VERSION 5.8 ;
BUSBITCHARS "[]" ;
DIVIDERCHAR "/" ;
UNITS
    DATABASE MICRONS 1000 ;
END UNITS

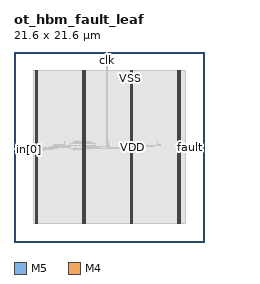
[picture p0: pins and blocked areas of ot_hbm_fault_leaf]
MACRO ot_hbm_fault_leaf
  FOREIGN ot_hbm_fault_leaf 0 0 ;
  CLASS BLOCK ;
  SIZE 21.6 BY 21.6 ;
  PIN clk
    DIRECTION INPUT ;
    USE SIGNAL ;
    PORT
      LAYER M5 ;
        RECT  10.512 21.516 10.536 21.6 ;
    END
  END clk
  PIN fault
    DIRECTION OUTPUT ;
    USE SIGNAL ;
    PORT
      LAYER M4 ;
        RECT  21.516 10.704 21.6 10.728 ;
    END
    PORT
      LAYER M4 ;
        RECT  21.481 10.704 21.564 10.728 ;
    END
  END fault
  PIN in[0]
    DIRECTION INPUT ;
    USE SIGNAL ;
    PORT
      LAYER M4 ;
        RECT  0 10.512 0.084 10.536 ;
    END
  END in[0]
  PIN in[1]
    DIRECTION INPUT ;
    USE SIGNAL ;
    PORT
      LAYER M4 ;
        RECT  0 10.608 0.084 10.632 ;
    END
  END in[1]
  PIN in[2]
    DIRECTION INPUT ;
    USE SIGNAL ;
    PORT
      LAYER M4 ;
        RECT  0 10.704 0.084 10.728 ;
    END
  END in[2]
  PIN in[3]
    DIRECTION INPUT ;
    USE SIGNAL ;
    PORT
      LAYER M4 ;
        RECT  0 10.8 0.084 10.824 ;
    END
  END in[3]
  PIN rst_n
    DIRECTION INPUT ;
    USE SIGNAL ;
    PORT
      LAYER M5 ;
        RECT  10.608 21.516 10.632 21.6 ;
    END
  END rst_n
  PIN VDD
    DIRECTION INOUT ;
    USE POWER ;
    PORT
      LAYER M5 ;
        RECT  18.792 2.151 18.912 19.449 ;
        RECT  13.392 2.151 13.512 19.449 ;
        RECT  7.992 2.151 8.112 19.449 ;
        RECT  2.592 2.151 2.712 19.449 ;
    END
  END VDD
  PIN VSS
    DIRECTION INOUT ;
    USE GROUND ;
    PORT
      LAYER M5 ;
        RECT  18.6 2.137 18.72 19.463 ;
        RECT  13.2 2.137 13.32 19.463 ;
        RECT  7.8 2.137 7.92 19.463 ;
        RECT  2.4 2.137 2.52 19.463 ;
    END
  END VSS
  # OT_OBS_CLOSED layer=M5 d_um=1.536 added=0
  OBS
    LAYER RVTN ;
     RECT  2.16 2.16 19.44 2.295 ;
     RECT  2.16 2.565 19.44 2.835 ;
     RECT  2.16 3.105 19.44 3.375 ;
     RECT  2.16 3.645 19.44 3.915 ;
     RECT  2.16 4.185 19.44 4.455 ;
     RECT  2.16 4.725 19.44 4.995 ;
     RECT  2.16 5.265 19.44 5.535 ;
     RECT  2.16 5.805 19.44 6.075 ;
     RECT  2.16 6.345 19.44 6.615 ;
     RECT  2.16 6.885 19.44 7.155 ;
     RECT  2.16 7.425 19.44 7.695 ;
     RECT  2.16 7.965 19.44 8.235 ;
     RECT  2.16 8.505 19.44 8.775 ;
     RECT  2.16 9.045 19.44 9.315 ;
     RECT  2.16 9.585 19.44 9.855 ;
     RECT  2.16 10.125 19.44 10.395 ;
     RECT  2.16 10.665 19.44 10.935 ;
     RECT  2.16 11.205 19.44 11.475 ;
     RECT  2.16 11.745 19.44 12.015 ;
     RECT  2.16 12.285 19.44 12.555 ;
     RECT  2.16 12.825 19.44 13.095 ;
     RECT  2.16 13.365 19.44 13.635 ;
     RECT  2.16 13.905 19.44 14.175 ;
     RECT  2.16 14.445 19.44 14.715 ;
     RECT  2.16 14.985 19.44 15.255 ;
     RECT  2.16 15.525 19.44 15.795 ;
     RECT  2.16 16.065 19.44 16.335 ;
     RECT  2.16 16.605 19.44 16.875 ;
     RECT  2.16 17.145 19.44 17.415 ;
     RECT  2.16 17.685 19.44 17.955 ;
     RECT  2.16 18.225 19.44 18.495 ;
     RECT  2.16 18.765 19.44 19.035 ;
     RECT  2.16 19.305 19.44 19.44 ;
    LAYER RVTP ;
     RECT  2.16 2.295 19.44 2.565 ;
     RECT  2.16 2.835 19.44 3.105 ;
     RECT  2.16 3.375 19.44 3.645 ;
     RECT  2.16 3.915 19.44 4.185 ;
     RECT  2.16 4.455 19.44 4.725 ;
     RECT  2.16 4.995 19.44 5.265 ;
     RECT  2.16 5.535 19.44 5.805 ;
     RECT  2.16 6.075 19.44 6.345 ;
     RECT  2.16 6.615 19.44 6.885 ;
     RECT  2.16 7.155 19.44 7.425 ;
     RECT  2.16 7.695 19.44 7.965 ;
     RECT  2.16 8.235 19.44 8.505 ;
     RECT  2.16 8.775 19.44 9.045 ;
     RECT  2.16 9.315 19.44 9.585 ;
     RECT  2.16 9.855 19.44 10.125 ;
     RECT  2.16 10.395 19.44 10.665 ;
     RECT  2.16 10.935 19.44 11.205 ;
     RECT  2.16 11.475 19.44 11.745 ;
     RECT  2.16 12.015 19.44 12.285 ;
     RECT  2.16 12.555 19.44 12.825 ;
     RECT  2.16 13.095 19.44 13.365 ;
     RECT  2.16 13.635 19.44 13.905 ;
     RECT  2.16 14.175 19.44 14.445 ;
     RECT  2.16 14.715 19.44 14.985 ;
     RECT  2.16 15.255 19.44 15.525 ;
     RECT  2.16 15.795 19.44 16.065 ;
     RECT  2.16 16.335 19.44 16.605 ;
     RECT  2.16 16.875 19.44 17.145 ;
     RECT  2.16 17.415 19.44 17.685 ;
     RECT  2.16 17.955 19.44 18.225 ;
     RECT  2.16 18.495 19.44 18.765 ;
     RECT  2.16 19.035 19.44 19.305 ;
    LAYER M1 ;
     RECT  2.16 2.151 19.44 19.449 ;
    LAYER M2 ;
     RECT  2.16 2.151 19.44 19.449 ;
     RECT  19.44 10.836 21.515 10.854 ;
    LAYER M3 ;
     RECT  2.415 2.143 2.505 2.413 ;
     RECT  7.815 2.143 7.905 2.413 ;
     RECT  13.215 2.143 13.305 2.413 ;
     RECT  18.615 2.143 18.705 2.413 ;
     RECT  2.415 2.413 2.697 10.399 ;
     RECT  2.415 10.399 3.33 10.471 ;
     RECT  7.815 2.413 8.097 10.471 ;
     RECT  2.415 10.471 4.518 10.507 ;
     RECT  6.804 10.399 6.822 10.561 ;
     RECT  7.815 10.471 8.19 10.561 ;
     RECT  13.215 2.413 13.497 10.561 ;
     RECT  2.304 10.507 4.518 10.589 ;
     RECT  2.304 10.589 2.697 10.597 ;
     RECT  3.996 10.589 4.518 10.597 ;
     RECT  6.804 10.561 8.19 10.597 ;
     RECT  6.804 10.597 8.91 10.603 ;
     RECT  3.996 10.597 4.698 10.633 ;
     RECT  6.408 10.603 8.91 10.633 ;
     RECT  6.408 10.633 8.982 10.696 ;
     RECT  12.348 10.561 13.497 10.696 ;
     RECT  3.996 10.633 4.95 10.705 ;
     RECT  6.012 10.696 8.982 10.705 ;
     RECT  12.24 10.696 13.497 10.733 ;
     RECT  3.996 10.705 8.982 10.741 ;
     RECT  2.268 10.597 2.697 10.829 ;
     RECT  10.224 10.699 10.242 10.831 ;
     RECT  3.996 10.741 9.306 10.843 ;
     RECT  10.224 10.831 10.854 10.843 ;
     RECT  21.492 10.699 21.51 10.859 ;
     RECT  3.996 10.843 10.854 10.877 ;
     RECT  4.5 10.877 10.854 10.895 ;
     RECT  12.528 10.733 13.497 10.925 ;
     RECT  15.804 10.891 15.822 10.939 ;
     RECT  10.548 10.895 10.854 10.967 ;
     RECT  15.804 10.939 16.362 10.975 ;
     RECT  4.5 10.895 9.306 11.003 ;
     RECT  15.804 10.975 16.65 11.003 ;
     RECT  4.5 11.003 5.706 11.039 ;
     RECT  5.184 11.039 5.706 11.129 ;
     RECT  16.344 11.003 16.65 11.129 ;
     RECT  6.444 11.003 9.306 11.165 ;
     RECT  6.768 11.165 9.306 11.201 ;
     RECT  6.768 11.201 8.982 11.309 ;
     RECT  5.688 11.129 5.706 11.399 ;
     RECT  6.768 11.309 8.55 11.399 ;
     RECT  10.548 10.967 10.782 11.399 ;
     RECT  16.344 11.129 16.362 11.399 ;
     RECT  7.056 11.399 8.55 11.435 ;
     RECT  10.548 11.399 10.566 11.549 ;
     RECT  7.056 11.435 7.074 11.579 ;
     RECT  2.415 10.829 2.697 19.187 ;
     RECT  7.815 11.435 8.097 19.187 ;
     RECT  13.215 10.925 13.497 19.187 ;
     RECT  18.615 2.413 18.897 19.187 ;
     RECT  2.415 19.187 2.505 19.457 ;
     RECT  7.815 19.187 7.905 19.457 ;
     RECT  13.215 19.187 13.305 19.457 ;
     RECT  18.615 19.187 18.705 19.457 ;
    LAYER M4 ;
     RECT  0.084 10.512 2.408 10.536 ;
     RECT  0.06 10.536 2.408 10.608 ;
     RECT  0.084 10.608 2.408 10.632 ;
     RECT  0.06 10.632 2.408 10.704 ;
     RECT  0.084 10.704 2.408 10.728 ;
     RECT  0.06 10.728 2.408 10.8 ;
     RECT  0.084 10.8 2.408 10.824 ;
     RECT  2.408 2.148 2.512 19.452 ;
     RECT  2.512 2.418 2.704 19.182 ;
     RECT  2.704 10.704 3.985 10.728 ;
     RECT  3.985 10.704 6.325 10.872 ;
     RECT  6.325 10.704 6.397 10.968 ;
     RECT  6.397 10.608 7.009 10.968 ;
     RECT  7.009 10.608 7.808 11.016 ;
     RECT  7.808 2.148 7.912 19.452 ;
     RECT  7.912 2.418 8.104 19.182 ;
     RECT  8.104 10.608 9.889 10.728 ;
     RECT  9.889 10.608 10.537 10.872 ;
     RECT  10.537 10.608 10.643 11.544 ;
     RECT  10.643 10.608 12.517 10.728 ;
     RECT  12.517 10.608 13.208 10.92 ;
     RECT  13.208 2.148 13.312 19.452 ;
     RECT  13.312 2.418 13.504 19.182 ;
     RECT  13.504 10.896 15.833 10.92 ;
     RECT  18.608 2.148 18.712 19.452 ;
     RECT  18.712 2.418 18.904 19.182 ;
    LAYER M5 ;
     RECT  2.4 2.137 2.52 2.151 ;
     RECT  7.8 2.137 7.92 2.151 ;
     RECT  13.2 2.137 13.32 2.151 ;
     RECT  18.6 2.137 18.72 2.151 ;
     RECT  10.512 10.837 10.536 11.509 ;
     RECT  2.4 2.151 2.712 19.449 ;
     RECT  7.8 2.151 8.112 19.449 ;
     RECT  13.2 2.151 13.512 19.449 ;
     RECT  18.6 2.151 18.912 19.449 ;
     RECT  2.4 19.449 2.52 19.463 ;
     RECT  7.8 19.449 7.92 19.463 ;
     RECT  13.2 19.449 13.32 19.463 ;
     RECT  18.6 19.449 18.72 19.463 ;
     RECT  10.512 11.509 10.632 21.516 ;
     RECT  10.536 21.516 10.608 21.584 ;
  END
END ot_hbm_fault_leaf
END LIBRARY
